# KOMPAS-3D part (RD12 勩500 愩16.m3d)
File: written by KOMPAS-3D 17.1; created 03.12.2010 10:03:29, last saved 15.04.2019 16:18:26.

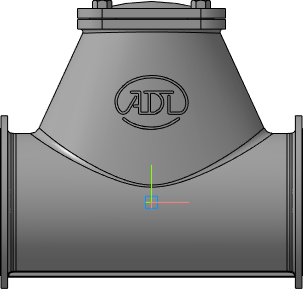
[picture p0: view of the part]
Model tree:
1. Плоскость XY
2. Плоскость ZX
3. Плоскость ZY
4. Ось X
5. Ось Y
6. Ось Z
7. Начало координат
8. Операция без истории:2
